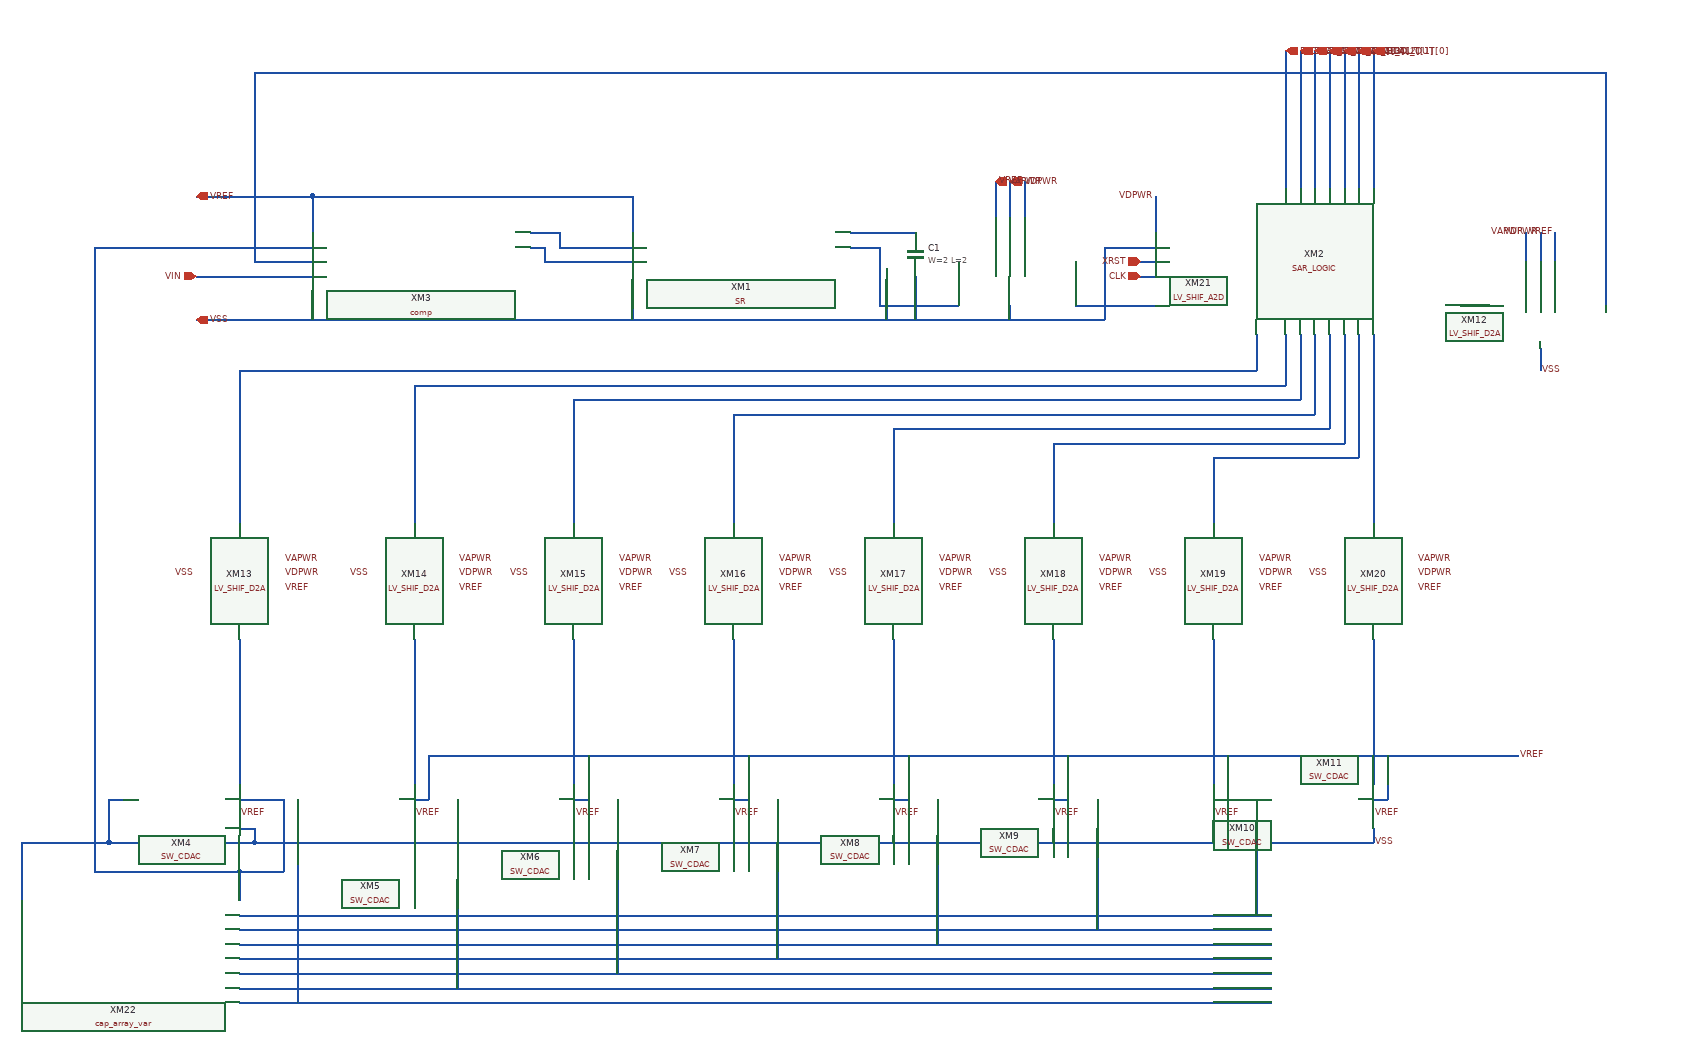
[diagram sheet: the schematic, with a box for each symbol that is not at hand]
v {xschem version=3.4.8RC file_version=1.3}
G {}
K {}
V {}
S {}
F {}
E {}
N 2740 -1200 2760 -1200 {
lab=CLK}
N 2740 -1220 2760 -1220 {
lab=XRST}
N 1900 -1260 1940 -1260 {
lab=#net1}
N 1900 -1240 1920 -1240 {
lab=#net2}
N 1500 -320 2920 -320 {
lab=#net3}
N 1500 -300 2920 -300 {
lab=#net4}
N 1500 -280 2920 -280 {
lab=#net5}
N 1500 -260 2920 -260 {
lab=#net6}
N 1500 -240 2920 -240 {
lab=#net7}
N 1500 -220 2920 -220 {
lab=#net8}
N 1500 -200 2920 -200 {
lab=#net9}
N 1740 -680 1740 -500 {
lab=#net10}
N 1960 -660 1960 -500 {
lab=#net11}
N 2180 -640 2180 -500 {
lab=#net12}
N 2400 -620 2400 -500 {
lab=#net13}
N 2620 -600 2620 -500 {
lab=#net14}
N 2840 -580 2840 -500 {
lab=#net15}
N 3060 -690 3060 -500 {
lab=#net16}
N 1500 -700 1500 -500 {
lab=#net17}
N 1320 -480 1340 -480 {
lab=VSS}
N 1320 -480 1320 -420 {
lab=VSS}
N 1320 -420 1520 -420 {
lab=VSS}
N 1520 -440 1520 -420 {
lab=VSS}
N 1500 -440 1520 -440 {
lab=VSS}
N 1500 -380 1500 -340 {
lab=#net18}
N 1300 -380 1500 -380 {
lab=#net18}
N 1300 -900 1300 -380 {
lab=#net18}
N 1500 -480 1560 -480 {
lab=#net18}
N 1560 -480 1560 -380 {
lab=#net18}
N 1500 -380 1560 -380 {
lab=#net18}
N 1520 -1220 1600 -1220 {
lab=#net19}
N 1620 -1480 3380 -1480 {
lab=#net19}
N 3380 -1480 3380 -1160 {
lab=#net19}
N 2340 -1240 2380 -1240 {
lab=#net20}
N 2380 -1240 2380 -1160 {
lab=#net20}
N 2340 -1260 2420 -1260 {
lab=#net21}
N 1760 -540 3260 -540 {
lab=VREF}
N 1740 -480 1760 -480 {
lab=VREF}
N 1760 -540 1760 -480 {
lab=VREF}
N 1960 -480 1980 -480 {
lab=VREF}
N 1980 -540 1980 -480 {
lab=VREF}
N 2180 -480 2200 -480 {
lab=VREF}
N 2200 -540 2200 -480 {
lab=VREF}
N 2400 -480 2420 -480 {
lab=VREF}
N 2420 -540 2420 -480 {
lab=VREF}
N 2620 -480 2640 -480 {
lab=VREF}
N 2640 -540 2640 -480 {
lab=VREF}
N 2840 -480 2860 -480 {
lab=VREF}
N 2860 -540 2860 -480 {
lab=VREF}
N 3060 -480 3080 -480 {
lab=VREF}
N 3080 -540 3080 -480 {
lab=VREF}
N 1940 -1260 1940 -1240 {
lab=#net1}
N 2020 -480 2020 -240 {
lab=#net7}
N 1800 -480 1800 -220 {
lab=#net8}
N 1580 -480 1580 -200 {
lab=#net9}
N 2940 -1460 2940 -1320 {
lab=DIGITAL_OUT[5]}
N 2960 -1460 2960 -1320 {
lab=DIGITAL_OUT[4]}
N 2980 -1460 2980 -1320 {
lab=DIGITAL_OUT[3]}
N 3000 -1460 3000 -1320 {
lab=DIGITAL_OUT[2]}
N 3020 -1460 3020 -1320 {
lab=DIGITAL_OUT[1]}
N 3040 -1460 3040 -1320 {
lab=DIGITAL_OUT[0]}
N 3060 -1460 3060 -1320 {
lab=EOC}
N 1920 -1240 1920 -1220 {
lab=#net2}
N 1920 -1220 2040 -1220 {
lab=#net2}
N 1940 -1240 2040 -1240 {
lab=#net1}
N 2760 -1310 2760 -1260 {lab=VDPWR}
N 2040 -1310 2040 -1260 {lab=VREF}
N 1600 -1310 1600 -1260 {lab=VREF}
N 1590 -1140 2590 -1140 {lab=VSS}
N 2690 -1240 2760 -1240 {lab=VSS}
N 2040 -1200 2040 -1140 {lab=VSS}
N 1600 -1180 1600 -1140 {lab=VSS}
N 1520 -420 3060 -420 {lab=VSS}
N 3060 -440 3060 -420 {lab=VSS}
N 1740 -440 1740 -420 {lab=VSS}
N 1960 -440 1960 -420 {lab=VSS}
N 2180 -440 2180 -420 {lab=VSS}
N 2400 -440 2400 -420 {lab=VSS}
N 2620 -440 2620 -420 {lab=VSS}
N 1440 -1310 1580 -1310 {lab=VREF}
N 1490 -1200 1600 -1200 {lab=VIN}
N 2940 -1510 2940 -1460 {lab=DIGITAL_OUT[5]}
N 2960 -1510 2960 -1460 {lab=DIGITAL_OUT[4]}
N 2980 -1510 2980 -1460 {lab=DIGITAL_OUT[3]}
N 3000 -1510 3000 -1460 {lab=DIGITAL_OUT[2]}
N 3020 -1510 3020 -1460 {lab=DIGITAL_OUT[1]}
N 3040 -1510 3040 -1460 {lab=DIGITAL_OUT[0]}
N 3060 -1510 3060 -1460 {lab=EOC}
N 1440 -1200 1490 -1200 {lab=VIN}
N 1440 -1140 1590 -1140 {lab=VSS}
N 1200 -420 1320 -420 {lab=VSS}
N 1200 -420 1200 -340 {lab=VSS}
N 1580 -1310 1600 -1310 {lab=VREF}
N 1600 -1310 2040 -1310 {lab=VREF}
N 3180 -1160 3220 -1160 {lab=#net22}
N 3060 -700 3060 -690 {lab=#net16}
N 2840 -700 2840 -580 {lab=#net15}
N 2620 -700 2620 -600 {lab=#net14}
N 2400 -700 2400 -620 {lab=#net13}
N 2180 -700 2180 -640 {lab=#net12}
N 1960 -700 1960 -660 {lab=#net11}
N 1740 -700 1740 -680 {lab=#net10}
N 1500 -1070 1500 -860 {lab=#net23}
N 1500 -1070 2900 -1070 {lab=#net23}
N 2900 -1120 2900 -1070 {lab=#net23}
N 1740 -1050 1740 -860 {lab=#net24}
N 1740 -1050 2940 -1050 {lab=#net24}
N 2940 -1120 2940 -1050 {lab=#net24}
N 1960 -1030 1960 -860 {lab=#net25}
N 1960 -1030 2960 -1030 {lab=#net25}
N 2960 -1120 2960 -1030 {lab=#net25}
N 2180 -1010 2180 -860 {lab=#net26}
N 2180 -1010 2980 -1010 {lab=#net26}
N 2980 -1120 2980 -1010 {lab=#net26}
N 2400 -990 2400 -860 {lab=#net27}
N 2400 -990 3000 -990 {lab=#net27}
N 3000 -1120 3000 -990 {lab=#net27}
N 2620 -970 2620 -860 {lab=#net28}
N 2620 -970 3020 -970 {lab=#net28}
N 3020 -1120 3020 -970 {lab=#net28}
N 2840 -950 2840 -860 {lab=#net29}
N 2840 -950 3040 -950 {lab=#net29}
N 3040 -1120 3040 -950 {lab=#net29}
N 3060 -1120 3060 -860 {lab=#net30}
N 1300 -1240 1300 -900 {lab=#net18}
N 1300 -1240 1600 -1240 {lab=#net18}
N 1520 -1480 1520 -1220 {lab=#net19}
N 1520 -1480 1620 -1480 {lab=#net19}
N 2690 -1240 2690 -1140 {lab=VSS}
N 2590 -1140 2690 -1140 {lab=VSS}
N 2650 -1220 2650 -1160 {lab=#net31}
N 2650 -1160 2760 -1160 {lab=#net31}
N 2490 -1220 2490 -1160 {lab=#net20}
N 2380 -1160 2490 -1160 {lab=#net20}
N 2540 -1330 2540 -1280 {lab=VAPWR}
N 2560 -1330 2560 -1280 {lab=VDPWR}
N 2580 -1330 2580 -1280 {lab=VREF}
N 3270 -1260 3270 -1220 {lab=VAPWR}
N 3290 -1260 3290 -1220 {lab=VDPWR}
N 3310 -1260 3310 -1220 {lab=VREF}
N 2560 -1160 2560 -1140 {lab=VSS}
N 3290 -1100 3290 -1070 {lab=VSS}
N 2900 -480 2900 -320 {lab=#net3}
N 2680 -480 2680 -300 {lab=#net4}
N 2460 -480 2460 -280 {lab=#net5}
N 2240 -480 2240 -260 {lab=#net6}
N 2840 -440 2840 -420 {lab=VSS}
N 2420 -1260 2430 -1260 {lab=#net21}
N 2430 -1200 2430 -1140 {lab=VSS}
N 2390 -1210 2390 -1140 {lab=VSS}
C {devices/lab_pin.sym} 1500 -460 2 0 {name=p1 sig_type=std_logic lab=VREF}
C {devices/lab_pin.sym} 1740 -460 2 0 {name=p3 sig_type=std_logic lab=VREF}
C {devices/lab_pin.sym} 1960 -460 2 0 {name=p4 sig_type=std_logic lab=VREF}
C {devices/lab_pin.sym} 2180 -460 2 0 {name=p6 sig_type=std_logic lab=VREF}
C {devices/lab_pin.sym} 2400 -460 2 0 {name=p8 sig_type=std_logic lab=VREF}
C {devices/lab_pin.sym} 2620 -460 2 0 {name=p22 sig_type=std_logic lab=VREF}
C {devices/lab_pin.sym} 2840 -460 2 0 {name=p23 sig_type=std_logic lab=VREF}
C {devices/lab_pin.sym} 3060 -460 2 0 {name=p24 sig_type=std_logic lab=VREF}
C {SR.sym} 2190 -1230 0 0 {name=XM1
spiceprefix=X
}
C {SAR_LOGIC.sym} 2970 -1210 0 0 {name=XM2 prefix=SAR_LOGIC}
C {SW_CDAC.sym} 1500 -500 0 1 {name=XM4
spiceprefix=X}
C {SW_CDAC.sym} 1740 -500 0 1 {name=XM5
spiceprefix=X}
C {SW_CDAC.sym} 1960 -500 0 1 {name=XM6
spiceprefix=X}
C {SW_CDAC.sym} 2180 -500 0 1 {name=XM7
spiceprefix=X}
C {SW_CDAC.sym} 2400 -500 0 1 {name=XM8
spiceprefix=X}
C {SW_CDAC.sym} 2620 -500 0 1 {name=XM9
spiceprefix=X}
C {SW_CDAC.sym} 2840 -500 0 1 {name=XM10
spiceprefix=X}
C {SW_CDAC.sym} 3060 -500 0 1 {name=XM11
spiceprefix=X}
C {devices/iopin.sym} 1440 -1310 0 1 {name=p2 lab=VREF}
C {devices/iopin.sym} 1440 -1140 0 1 {name=p9 lab=VSS}
C {devices/lab_wire.sym} 3060 -420 2 0 {name=p10 sig_type=std_logic lab=VSS}
C {comp.sym} 1750 -1220 0 0 {name=XM3
spiceprefix=X}
C {devices/lab_pin.sym} 3260 -540 2 0 {name=p11 sig_type=std_logic lab=VREF}
C {devices/ipin.sym} 1440 -1200 0 0 {name=p12 lab=VIN}
C {devices/ipin.sym} 2740 -1200 0 0 {name=p13 lab=CLK}
C {devices/ipin.sym} 2740 -1220 0 0 {name=p5 lab=XRST}
C {devices/opin.sym} 2940 -1510 3 0 {name=p7 lab=DIGITAL_OUT[5]}
C {devices/opin.sym} 2960 -1510 3 0 {name=p14 lab=DIGITAL_OUT[4]}
C {devices/opin.sym} 2980 -1510 3 0 {name=p15 lab=DIGITAL_OUT[3]}
C {devices/opin.sym} 3000 -1510 3 0 {name=p16 lab=DIGITAL_OUT[2]}
C {devices/opin.sym} 3020 -1510 3 0 {name=p19 lab=DIGITAL_OUT[1]}
C {devices/opin.sym} 3040 -1510 3 0 {name=p20 lab=DIGITAL_OUT[0]}
C {devices/opin.sym} 3060 -1510 3 0 {name=p25 lab=EOC}
C {devices/iopin.sym} 2560 -1330 1 1 {name=p17 lab=VDPWR}
C {LV_SHIF_D2A.sym} 3360 -1100 0 0 {name=XM12
spiceprefix=X
}
C {LV_SHIF_D2A.sym} 1440 -720 1 0 {name=XM13
spiceprefix=X
}
C {LV_SHIF_D2A.sym} 1680 -720 1 0 {name=XM14
spiceprefix=X
}
C {LV_SHIF_D2A.sym} 1900 -720 1 0 {name=XM15
spiceprefix=X
}
C {LV_SHIF_D2A.sym} 2120 -720 1 0 {name=XM16
spiceprefix=X
}
C {LV_SHIF_D2A.sym} 2340 -720 1 0 {name=XM17
spiceprefix=X
}
C {LV_SHIF_D2A.sym} 2560 -720 1 0 {name=XM18
spiceprefix=X
}
C {LV_SHIF_D2A.sym} 2780 -720 1 0 {name=XM19
spiceprefix=X
}
C {LV_SHIF_D2A.sym} 3000 -720 1 0 {name=XM20
spiceprefix=X
}
C {LV_SHIF_A2D.sym} 2630 -1160 0 0 {name=XM21
spiceprefix=X
}
C {devices/iopin.sym} 2540 -1330 1 1 {name=p21 lab=VAPWR}
C {devices/lab_pin.sym} 2760 -1310 0 0 {name=p26 sig_type=std_logic lab=VDPWR}
C {devices/lab_pin.sym} 2580 -1330 3 1 {name=p27 sig_type=std_logic lab=VREF}
C {devices/lab_pin.sym} 3290 -1260 3 1 {name=p28 sig_type=std_logic lab=VDPWR}
C {devices/lab_pin.sym} 3310 -1260 3 1 {name=p29 sig_type=std_logic lab=VREF}
C {devices/lab_pin.sym} 3270 -1260 3 1 {name=p30 sig_type=std_logic lab=VAPWR}
C {devices/lab_wire.sym} 3290 -1070 2 0 {name=p18 sig_type=std_logic lab=VSS}
C {devices/lab_wire.sym} 3000 -790 2 1 {name=p31 sig_type=std_logic lab=VSS}
C {devices/lab_wire.sym} 2780 -790 2 1 {name=p32 sig_type=std_logic lab=VSS}
C {devices/lab_wire.sym} 2560 -790 2 1 {name=p33 sig_type=std_logic lab=VSS}
C {devices/lab_wire.sym} 2340 -790 2 1 {name=p34 sig_type=std_logic lab=VSS}
C {devices/lab_wire.sym} 2120 -790 2 1 {name=p35 sig_type=std_logic lab=VSS}
C {devices/lab_wire.sym} 1900 -790 2 1 {name=p36 sig_type=std_logic lab=VSS}
C {devices/lab_wire.sym} 1680 -790 2 1 {name=p37 sig_type=std_logic lab=VSS}
C {devices/lab_wire.sym} 1440 -790 2 1 {name=p38 sig_type=std_logic lab=VSS}
C {devices/lab_pin.sym} 3120 -770 2 0 {name=p39 sig_type=std_logic lab=VREF}
C {devices/lab_pin.sym} 3120 -790 0 1 {name=p40 sig_type=std_logic lab=VDPWR}
C {devices/lab_pin.sym} 3120 -810 0 1 {name=p41 sig_type=std_logic lab=VAPWR}
C {devices/lab_pin.sym} 2900 -770 2 0 {name=p42 sig_type=std_logic lab=VREF}
C {devices/lab_pin.sym} 2900 -790 0 1 {name=p43 sig_type=std_logic lab=VDPWR}
C {devices/lab_pin.sym} 2900 -810 0 1 {name=p44 sig_type=std_logic lab=VAPWR}
C {devices/lab_pin.sym} 2680 -770 2 0 {name=p45 sig_type=std_logic lab=VREF}
C {devices/lab_pin.sym} 2680 -790 0 1 {name=p46 sig_type=std_logic lab=VDPWR}
C {devices/lab_pin.sym} 2680 -810 0 1 {name=p47 sig_type=std_logic lab=VAPWR}
C {devices/lab_pin.sym} 2460 -770 2 0 {name=p48 sig_type=std_logic lab=VREF}
C {devices/lab_pin.sym} 2460 -790 0 1 {name=p49 sig_type=std_logic lab=VDPWR}
C {devices/lab_pin.sym} 2460 -810 0 1 {name=p50 sig_type=std_logic lab=VAPWR}
C {devices/lab_pin.sym} 2240 -770 2 0 {name=p51 sig_type=std_logic lab=VREF}
C {devices/lab_pin.sym} 2240 -790 0 1 {name=p52 sig_type=std_logic lab=VDPWR}
C {devices/lab_pin.sym} 2240 -810 0 1 {name=p53 sig_type=std_logic lab=VAPWR}
C {devices/lab_pin.sym} 2020 -770 2 0 {name=p54 sig_type=std_logic lab=VREF}
C {devices/lab_pin.sym} 2020 -790 0 1 {name=p55 sig_type=std_logic lab=VDPWR}
C {devices/lab_pin.sym} 2020 -810 0 1 {name=p56 sig_type=std_logic lab=VAPWR}
C {devices/lab_pin.sym} 1800 -770 2 0 {name=p57 sig_type=std_logic lab=VREF}
C {devices/lab_pin.sym} 1800 -790 0 1 {name=p58 sig_type=std_logic lab=VDPWR}
C {devices/lab_pin.sym} 1800 -810 0 1 {name=p59 sig_type=std_logic lab=VAPWR}
C {devices/lab_pin.sym} 1560 -770 2 0 {name=p60 sig_type=std_logic lab=VREF}
C {devices/lab_pin.sym} 1560 -790 0 1 {name=p61 sig_type=std_logic lab=VDPWR}
C {devices/lab_pin.sym} 1560 -810 0 1 {name=p62 sig_type=std_logic lab=VAPWR}
C {cap_array_var.sym} 1350 -270 0 0 {name=XM22
spiceprefix=X}
C {sky130_fd_pr/cap_var_hvt.sym} 2430 -1230 0 0 {name=C1 model=cap_var_hvt W=2 L=2 VM=1 spiceprefix=X}
